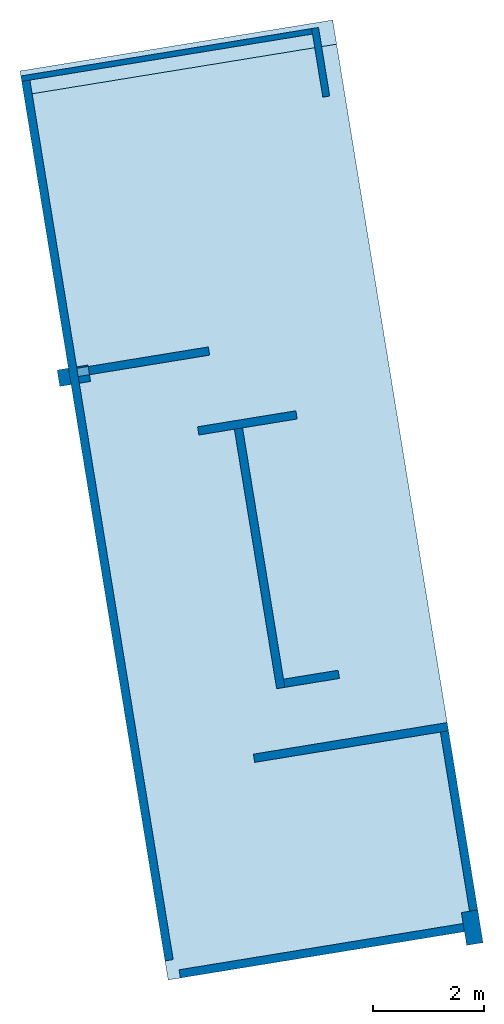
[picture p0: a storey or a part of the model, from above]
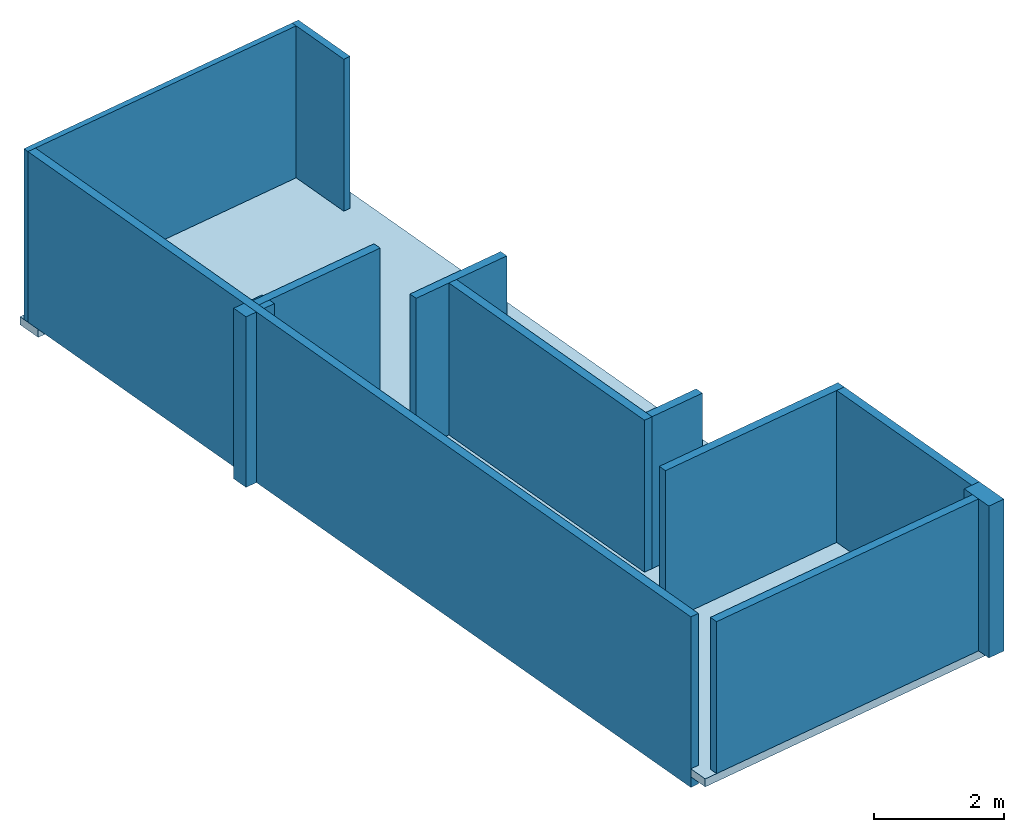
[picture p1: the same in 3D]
Properties of the parts of a building model (IFC2X3)

# File
Description: ViewDefinition [CoordinationView]
File name: BR002-350-101.1 (EDITED).IFC (Edited by Naviate Simple BIM 2022 version 6)
Time: 2026-03-27T07:42:59+01:00
Author: laura
Organization: Avinor
Written by: ODA SDAI 24.12
Made in: Autodesk Revit 25.4.41.14 (ENU) - IFC 25.4.0.27

# IfcProject, 01. Avinor Drift
LongName: Helikopter Terminal; Phase: Som bygget

# IfcSite, Default
RefLatitude: 60, 17, 20, 899658; RefLongitude: 5, 13, 37, 654037; RefElevation: 0 mm
Text - 01_Modellfil: br002-a-200-1-0001; 02_IfcSite: Bergen Lufthavn, Flesland
Other - Project Number: 01. Avinor Drift; Project Address: Bergen lufthavn Flesland; Category: Project Information; Project Status: Som bygget; Client Name: Avinor AS; Project Issue Date: 14.04.16; Project Name: Helikopter Terminal
Identity Data - Author: FDVU; Organization Name: Avinor AS; Workset: Project Info; Organization Description: D&I; Building Name: br002

# IfcBuilding, br002
LongName: br002
Pset_BuildingCommon - NumberOfStoreys: 9
Text - 01_Modellfil: br002-a-200-1-0001; 02_IfcSite: Bergen Lufthavn, Flesland
Other - Project Number: 01. Avinor Drift; Project Address: Bergen lufthavn Flesland; Category: Project Information; Project Status: Som bygget; Client Name: Avinor AS; Project Issue Date: 14.04.16; Project Name: Helikopter Terminal
Identity Data - Author: FDVU; Organization Name: Avinor AS; Workset: Project Info; Organization Description: D&I; Building Name: br002

# IfcBuildingStorey: Level:8mm Head (2)
In: br002
Other - Family and Type: Level: 8mm Head; Type Id: 305; Category: Levels; Family: Level; Type: 8mm Head
Graphics(Type) - Line Pattern: Centre; Symbol: M_Level Head - Circle; Color: 0; Symbol at End 1 Default: no; Symbol at End 2 Default: yes; Line Weight: 1
Identity Data - Structural: no; Building Story: yes; Workset: Shared Levels and Grids
Constraints(Type) - Elevation Base: Project Base Point
Identity Data(Type) - Workset: Level Types; Type Name: 8mm Head
Other(Type) - Category: Levels; Family Name: Level
Name | LongName = Identity Data, Name | Elevation (mm) | Computation Height (mm) | Constraints, Elevation (mm)
H01 | H01 | 3850 | 350 | 52210 | Pset_ProductRequirements - Name: H01; sets with these values: 2
Tak | Tak | 7600 | 0 | 55960 | Pset_AirSideSystemInformation - Name: Tak; sets with these values: 2

# IfcColumn: M_Rectangular Column:563 x 300 mm, M_Rectangular Column:563 x 300 mm:563376
In: H01
Type - PredefinedType: COLUMN; Material: Metal Deck
Type - Other - Category: Columns; Family Name: M_Rectangular Column
Type - Dimensions - Depth: 563 mm; Offset Base: 0 mm; Offset Top: 0 mm; Width: 300 mm
Type - Graphics - Coarse Scale Fill Color: 0
Type - Identity Data - OmniClass Number: 23.25.30.11.14.11; OmniClass Title: Columns; Type Name: 563 x 300 mm; Workset: Family : Columns : M_Rectangular Column
Phasing - Phase Created: Eksisterende
Other - Type Id: 564620; Family and Type: M_Rectangular Column: 563 x 300 mm; Family: M_Rectangular Column; Type: 563 x 300 mm
Dimensions - Volume: 0.308201 m3
Pset_QuantityTakeOff - Reference: 563 x 300 mm; sets with these values: 2
ePset_SimplebimBasicQuantities - Volume, net (Simplebim): 0.308201 m3; Depth (Simplebim): 563 mm; Weight, as steel (Simplebim): 2419.38 kg; Area, sides, net (Simplebim): 6.80525 m2; Width (Simplebim): 300 mm; Height (Simplebim): 3200 mm
ePset_LocationTool - Splitting: ORIGINAL
Constraints - Base Offset: 0 mm; Room Bounding: yes; Top Offset: 0 mm; Moves With Grids: yes; Top Level: H02; Base Level: H01; Level: H01
Pset_ColumnCommon - IsExternal: no; Reference: 563 x 300 mm
Identity Data - Workset: ARK
ePset_Simplebim - Assembly Level: Leaf

# IfcColumn: M_Rectangular Column:600 x 300 mm, M_Rectangular Column:600 x 300 mm:563728
In: H01
Type - PredefinedType: COLUMN; Material: Metal Deck
Type - Other - Category: Columns; Family Name: M_Rectangular Column
Type - Dimensions - Depth: 600 mm; Offset Base: 0 mm; Offset Top: 0 mm; Width: 300 mm
Type - Graphics - Coarse Scale Fill Color: 0
Type - Identity Data - OmniClass Number: 23.25.30.11.14.11; OmniClass Title: Columns; Type Name: 600 x 300 mm; Workset: Family : Columns : M_Rectangular Column
Phasing - Phase Created: Eksisterende
Identity Data - Workset: RIB
Constraints - Room Bounding: yes; Top Offset: 0 mm; Moves With Grids: yes; Top Level: H02; Base Level: H01; Level: H01; Base Offset: 350 mm
Pset_QuantityTakeOff - Reference: 600 x 300 mm; sets with these values: 2
Other - Family and Type: M_Rectangular Column: 600 x 300 mm; Type Id: 562945; Family: M_Rectangular Column; Type: 600 x 300 mm
ePset_SimplebimBasicQuantities - Area, sides, net (Simplebim): 5.13 m2; Volume, net (Simplebim): 0.513 m3; Weight, as steel (Simplebim): 4027.05 kg; Width (Simplebim): 300 mm; Depth (Simplebim): 600 mm; Height (Simplebim): 2850 mm
Dimensions - Volume: 0.513 m3
ePset_LocationTool - Splitting: ORIGINAL
Pset_ColumnCommon - IsExternal: no; Reference: 600 x 300 mm
ePset_Simplebim - Assembly Level: Leaf

# IfcRoof: Basic Roof:Sarnafil Tak, Basic Roof:Sarnafil Tak:751543
In: Tak
Material: Asphalt, Bitumen 20 mm, Rigid insulation 50 mm, Structure, Steel Bar Joist Layer 130 mm
Phasing - Phase Created: Eksisterende
Identity Data - Workset: ARK
Other - Type Id: 813923; Family: Basic Roof; Family and Type: Basic Roof: Sarnafil Tak; Category: Roofs; Type: Sarnafil Tak
Constraints - Related to Mass: no; Room Bounding: no; Base Offset From Level: 0 mm; Cutoff Offset: 0 mm; Base Level: Tak
Construction - Rafter or Truss: Truss; Rafter Cut: Plumb Cut; Fascia Depth: 0 mm; Maximum Ridge Height: 7800 mm
ePset_SimplebimBasicQuantities - Volume, net (Simplebim): 258.627 m3; Height: 200 mm; Width: 38150 mm; Length: 40660 mm
ePset_Simplebim - Assembly Level: Topmost
Pset_QuantityTakeOff - Reference: Sarnafil Tak
Dimensions - Area: 1293.14 m2; Volume: 258.627 m3; Slope: 0; Thickness: 200 mm
Pset_RoofCommon - TotalArea: 1293.14 m2; ProjectedArea: 1410.86 m2; IsExternal: yes; Reference: Sarnafil Tak

# IfcSlab: Basic Roof:Sarnafil Tak, Basic Roof:Sarnafil Tak:751543:1
In: Tak
Type - PredefinedType: ROOF
Type - Other - Category: Roofs; Family Name: Basic Roof
Type - Construction - Default Thickness: 200 mm
Type - Graphics - Coarse Scale Fill Color: 0
Type - Identity Data - Type Name: Sarnafil Tak; Workset: Roof Types
Type - Analytical Properties - Absorptance: 0.7; Roughness: 3; Heat Transfer Coefficient (U): 0.150467 W/K/m2; Thermal Mass: 40991; Thermal Resistance (R): 6.64596
Type - Pset_SlabCommon - ThermalTransmittance: 0.150467 W/K/m2
ePset_Simplebim - Assembly Level: Leaf
Pset_SlabCommon - IsExternal: yes; Reference: Sarnafil Tak
Pset_ReinforcementBarPitchOfSlab - Reference: Sarnafil Tak; sets with these values: 2
ePset_LocationTool - Splitting: RESULT
ePset_SimplebimBasicQuantities - Volume, net (Simplebim): 18.1 m3; Area, sides, net (Simplebim): 8.7 m2; Perimeter (Simplebim): 43500 mm; Thickness (Simplebim): 200 mm; Area, top, net (Simplebim): 90.5 m2; Area, largest surface, net (Simplebim): 90.5 m2

# IfcSlab: Floor:Betong 150mm (2)
In: H01
Type - PredefinedType: FLOOR; Material: Concrete, Cast In Situ 150 mm
Type - Other - Category: Floors; Family Name: Floor
Type - Construction - Function: Interior; Default Thickness: 150 mm
Type - Graphics - Coarse Scale Fill Color: 0
Type - Identity Data - Type Name: Betong 150mm; Workset: Floor Types
Type - Materials and Finishes - Structural Material: Concrete, Cast In Situ
Type - Analytical Properties - Absorptance: 0.7; Roughness: 3; Heat Transfer Coefficient (U): 6.97333 W/K/m2; Thermal Mass: 226665; Thermal Resistance (R): 0.143403
Type - Pset_SlabCommon - ThermalTransmittance: 6.97333 W/K/m2
ePset_Simplebim - Assembly Level: Leaf
ePset_LocationTool - Splitting: RESULT
Identity Data - Workset: ARK; Has Association: no
Other - Type: Betong 150mm; Family and Type: Floor: Betong 150mm; Type Id: 339; Family: Floor
Phasing - Phase Created: Eksisterende
Structural - Structural: no
Pset_SlabCommon - LoadBearing: no; IsExternal: no; Reference: Betong 150mm
Pset_QuantityTakeOff - Reference: Betong 150mm; sets with these values: 2
Constraints - Related to Mass: no; Room Bounding: yes; Level: H01
ePset_SimplebimBasicQuantities - Thickness (Simplebim): 150 mm
Name (Floor:Betong 150mm:...) | Perimeter (Simplebim) (mm) | Area, sides, net (Simplebim) (m2) | Area, top, net (Simplebim) (m2) | Area, largest surface, net (Simplebim) (m2) | Volume, net (Simplebim) (m3)
452084 | 12334.1 | 1.85011 | 2.53044 | 2.53045 | 0.379567
748018 | 44550 | 6.6825 | 94.7487 | 94.7488 | 14.2123

# IfcWall: Basic Wall:E 01 100 mm Innervegg, Basic Wall:E 01 100 mm Innervegg:560488
In: H01
Type - PredefinedType: STANDARD; Material: Gypsum Wall Board 13 mm, Structure, Timber Joist/Rafter Layer 74 mm, Gypsum Wall Board 13 mm
Type - Other - Category: Walls; Family Name: Basic Wall
Type - Construction - Function: Interior; Width: 100 mm; Wrapping at Ends: Exterior; Wrapping at Inserts: Both
Type - Graphics - Coarse Scale Fill Color: 0
Type - Identity Data - Type Mark: E01; Type Name: E 01 100 mm Innervegg; Workset: Wall Types
Type - Materials and Finishes - Structural Material: Structure, Timber Joist/Rafter Layer
Type - Analytical Properties - Absorptance: 0.7; Heat Transfer Coefficient (U): 0.333333 W/K/m2; Roughness: 3; Thermal Mass: 24113.1; Thermal Resistance (R): 3
Type - Pset_WallCommon - ThermalTransmittance: 0.333333 W/K/m2
ePset_Simplebim - Assembly Level: Leaf
Other - Family and Type: Basic Wall: E 01 100 mm Innervegg; Family: Basic Wall; Type: E 01 100 mm Innervegg; Type Id: 455070
Identity Data - Workset: ARK
Pset_WallCommon - Reference: E 01 100 mm Innervegg; IsExternal: no; ExtendToStructure: no; LoadBearing: no
Constraints - Base is Attached: no; Related to Mass: no; Room Bounding: yes; Top is Attached: no; Base Constraint: H01; Location Line: Finish Face: Interior; Top Constraint: Up to level: H02
Structural - Structural Usage: Non-bearing; Structural: no
ePset_SimplebimBasicQuantities - Volume, net (Simplebim): 1.70368 m3; Area, side, gross, average (Simplebim): 17.0368 m2; Area, side, net, average (Simplebim): 17.0368 m2; Area, largest surface, net (Simplebim): 17.0368 m2; Area, side, net, smaller (Simplebim): 17.0368 m2; Area, side, gross, smaller (Simplebim): 17.0368 m2; Area, side, net, larger (Simplebim): 17.0368 m2; Area, side, gross, larger (Simplebim): 17.0368 m2; Area, side, gross, AABB (Simplebim): 17.0368 m2; Thickness (Simplebim): 100 mm; Height (Simplebim): 3200 mm; Length (Simplebim): 5324 mm
Phasing - Phase Created: Eksisterende
Pset_QuantityTakeOff - Reference: E 01 100 mm Innervegg; sets with these values: 2
ePset_LocationTool - Splitting: RESULT
Cross-Section Definition - Cross-Section: Vertical

# IfcWall: Basic Wall:E 05 Betong 150 mm, Basic Wall:E 05 Betong 150 mm:811328
In: Tak
Type - PredefinedType: STANDARD; Material: Concrete, Cast In Situ 150 mm
Type - Other - Category: Walls; Family Name: Basic Wall
Type - Construction - Function: Exterior; Width: 150 mm; Wrapping at Ends: Exterior; Wrapping at Inserts: Both
Type - Graphics - Coarse Scale Fill Color: 12632256; Coarse Scale Fill Pattern: <Solid fill>
Type - Identity Data - Type Mark: E05 150mm; Type Name: E 05 Betong 150 mm; Workset: Wall Types
Type - Materials and Finishes - Structural Material: Concrete, Cast In Situ
Type - Analytical Properties - Absorptance: 0.7; Heat Transfer Coefficient (U): 6.97333 W/K/m2; Roughness: 3; Thermal Mass: 226665; Thermal Resistance (R): 0.143403
Type - Pset_WallCommon - ThermalTransmittance: 6.97333 W/K/m2
ePset_Simplebim - Assembly Level: Leaf
Identity Data - Workset: ARK
Constraints - Location Line: Wall Centerline; Base is Attached: no; Related to Mass: no; Room Bounding: yes; Top is Attached: no; Base Constraint: Tak; Top Constraint: Up to level: Tak
Pset_QuantityTakeOff - Reference: E 05 Betong 150 mm; sets with these values: 2
ePset_LocationTool - Splitting: RESULT
Structural - Structural Usage: Non-bearing; Structural: no
Phasing - Phase Created: Eksisterende
ePset_SimplebimBasicQuantities - Area, side, gross, larger (Simplebim): 2.57625 m2; Area, side, net, larger (Simplebim): 2.57625 m2; Area, side, gross, smaller (Simplebim): 2.57625 m2; Area, side, net, smaller (Simplebim): 2.57625 m2; Area, largest surface, net (Simplebim): 2.57625 m2; Area, side, net, average (Simplebim): 2.57625 m2; Area, side, gross, average (Simplebim): 2.57625 m2; Area, side, gross, AABB (Simplebim): 2.57625 m2; Thickness (Simplebim): 150 mm; Height (Simplebim): 450 mm; Length (Simplebim): 5725 mm; Volume, net (Simplebim): 0.386437 m3
Other - Family: Basic Wall; Type Id: 442479; Family and Type: Basic Wall: E 05 Betong 150 mm; Type: E 05 Betong 150 mm
Pset_WallCommon - IsExternal: yes; ExtendToStructure: no; LoadBearing: no; Reference: E 05 Betong 150 mm
Cross-Section Definition - Cross-Section: Vertical

# IfcWallStandardCase: Basic Wall:A 03 150 mm Planja Sand. (7)
In: H01
Type - PredefinedType: STANDARD; Material: Metal Deck 5 mm, Polyurethane Foam 140 mm, Metal Deck 5 mm
Type - Other - Category: Walls; Family Name: Basic Wall
Type - Construction - Function: Exterior; Width: 150 mm; Wrapping at Ends: Exterior; Wrapping at Inserts: Both
Type - Graphics - Coarse Scale Fill Color: 12632256; Coarse Scale Fill Pattern: <Solid fill>
Type - Identity Data - Type Mark: A03; Type Name: A 03 150 mm Planja Sand.; Workset: Wall Types
Type - Materials and Finishes - Structural Material: Polyurethane Foam
Type - Analytical Properties - Absorptance: 0.7; Heat Transfer Coefficient (U): 0.22856 W/K/m2; Roughness: 3; Thermal Mass: 45179.5; Thermal Resistance (R): 4.37522
Type - Pset_WallCommon - ThermalTransmittance: 0.22856 W/K/m2
ePset_Simplebim - Assembly Level: Leaf
ePset_LocationTool - Splitting: ORIGINAL
Identity Data - Workset: ARK
Pset_QuantityTakeOff - Reference: A 03 150 mm Planja Sand.; sets with these values: 2
Constraints - Location Line: Wall Centerline; Base Extension Distance: 0 mm; Base is Attached: no; Related to Mass: no; Room Bounding: yes; Top Extension Distance: 0 mm; Top is Attached: no; Top Offset: 0 mm; Base Constraint: H01; Top Constraint: Up to level: H02
Structural - Structural Usage: Non-bearing; Structural: no
Phasing - Phase Created: Eksisterende
Pset_WallCommon - Reference: A 03 150 mm Planja Sand.; IsExternal: yes; ExtendToStructure: no; LoadBearing: no
Other - Family: Basic Wall; Type: A 03 150 mm Planja Sand.; Family and Type: Basic Wall: A 03 150 mm Planja Sand.; Type Id: 562544
Cross-Section Definition - Cross-Section: Vertical
ePset_SimplebimBasicQuantities - Thickness (Simplebim): 150 mm
Name (Basic Wall:A 03 150 mm Planja Sand.:...) | Base Offset (mm) | Unconnected Height (mm) = Height (Simplebim) (mm) | Volume (m3) = Volume, net (Simplebim) (m3) | Area (m2) = Area, side, gross, AABB (Simplebim) (m2) | Length (mm) | Area, side, gross, larger (Simplebim) (m2) = Area, side, net, larger (Simplebim) (m2) = Area, side, gross, smaller (Simplebim) (m2) = Area, side, net, smaller (Simplebim) (m2) = Area, largest surface, net (Simplebim) (m2) = Area, side, net, average (Simplebim) (m2) = Area, side, gross, average (Simplebim) (m2) | Length (Simplebim) (mm)
562806 | 0 | 3200 | 7.728 | 51.52 | 16150 | 51.52 | 16100
564712 | 350 | 2850 | 1.02878 | 6.85852 | 2481.5 | 6.85853 | 2406.5
564821 | 350 | 2850 | 0.7695 | 5.13 | 1800 | 5.13 | 1800
564865 | 350 | 2850 | 2.03062 | 13.5375 | 4750 | 13.5375 | 4750
564906 | 350 | 2850 | 0.4275 | 2.85 | 1075 | 2.85 | 1000
564973 | 350 | 2850 | 1.51669 | 10.1113 | 3472.81 | 10.1113 | 3547.81
565062 | 350 | 2850 | 1.4022 | 9.348 | 3355 | 9.348 | 3280

# IfcWallStandardCase: Basic Wall:B 09 126mm Halvvegg, Basic Wall:B 09 126mm Halvvegg:560303
In: H01
Type - PredefinedType: STANDARD; Material: Gypsum Wall Board 15 mm, Structure, Timber Joist/Rafter Layer 96 mm, Gypsum Wall Board 15 mm
Type - Other - Category: Walls; Family Name: Basic Wall
Type - Construction - Function: Interior; Width: 126 mm; Wrapping at Inserts: Do not wrap
Type - Graphics - Coarse Scale Fill Color: 0
Type - Identity Data - Type Mark: B09; Type Name: B 09 126mm Halvvegg; Workset: Wall Types
Type - Materials and Finishes - Structural Material: Structure, Timber Joist/Rafter Layer
Type - Analytical Properties - Absorptance: 0.7; Heat Transfer Coefficient (U): 0.257324 W/K/m2; Roughness: 3; Thermal Mass: 27835.6; Thermal Resistance (R): 3.88615
Type - Pset_WallCommon - ThermalTransmittance: 0.257324 W/K/m2
Constraints - Base Extension Distance: 0 mm; Base is Attached: no; Base Offset: 0 mm; Related to Mass: no; Room Bounding: yes; Top Extension Distance: 0 mm; Top is Attached: no; Top Offset: 0 mm; Base Constraint: H01; Location Line: Finish Face: Interior; Unconnected Height: 3200 mm; Top Constraint: Up to level: H02
ePset_Simplebim - Assembly Level: Leaf
Identity Data - Workset: ARK
Other - Type: B 09 126mm Halvvegg; Family: Basic Wall; Type Id: 559783; Family and Type: Basic Wall: B 09 126mm Halvvegg
Pset_WallCommon - Reference: B 09 126mm Halvvegg; IsExternal: no; ExtendToStructure: no; LoadBearing: no
Structural - Structural Usage: Non-bearing; Structural: no
Phasing - Phase Created: Eksisterende
ePset_SimplebimBasicQuantities - Height (Simplebim): 3200 mm; Length (Simplebim): 1255.99 mm; Volume, net (Simplebim): 0.506415 m3; Thickness (Simplebim): 126 mm; Area, largest surface, net (Simplebim): 4.01917 m2; Area, side, net, average (Simplebim): 4.01917 m2; Area, side, gross, average (Simplebim): 4.01917 m2; Area, side, gross, larger (Simplebim): 4.01917 m2; Area, side, net, larger (Simplebim): 4.01917 m2; Area, side, gross, smaller (Simplebim): 4.01917 m2; Area, side, net, smaller (Simplebim): 4.01917 m2; Area, side, gross, AABB (Simplebim): 4.01917 m2
Pset_QuantityTakeOff - Reference: B 09 126mm Halvvegg; sets with these values: 2
ePset_LocationTool - Splitting: ORIGINAL
Dimensions - Length: 1205.99 mm; Volume: 0.506415 m3; Area: 4.01917 m2
Cross-Section Definition - Cross-Section: Vertical

# IfcWallStandardCase: Basic Wall:E 01 150 mm Innervegg, Basic Wall:E 01 150 mm Innervegg:565798
In: H01
Type - PredefinedType: STANDARD; Material: Gypsum Wall Board 13 mm, Gypsum Wall Board 13 mm, Rock Wool 49 mm, Rock Wool(1) 49 mm, Gypsum Wall Board 13 mm, Gypsum Wall Board 13 mm
Type - Other - Category: Walls; Family Name: Basic Wall
Type - Construction - Function: Interior; Width: 150 mm; Wrapping at Ends: Exterior; Wrapping at Inserts: Both
Type - Graphics - Coarse Scale Fill Color: 0
Type - Identity Data - Type Mark: E01 150mm; Type Name: E 01 150 mm Innervegg; Workset: Wall Types
Type - Materials and Finishes - Structural Material: Rock Wool
Type - Analytical Properties - Absorptance: 0.7; Heat Transfer Coefficient (U): 0.337569 W/K/m2; Roughness: 3; Thermal Mass: 61964; Thermal Resistance (R): 2.96235
Type - Pset_WallCommon - ThermalTransmittance: 0.337569 W/K/m2
ePset_Simplebim - Assembly Level: Leaf
Identity Data - Workset: ARK
ePset_SimplebimBasicQuantities - Height (Simplebim): 2850 mm; Thickness (Simplebim): 150 mm; Length (Simplebim): 5200 mm; Area, side, gross, average (Simplebim): 14.82 m2; Area, side, net, average (Simplebim): 14.82 m2; Area, largest surface, net (Simplebim): 14.82 m2; Area, side, net, smaller (Simplebim): 14.82 m2; Area, side, gross, smaller (Simplebim): 14.82 m2; Area, side, net, larger (Simplebim): 14.82 m2; Area, side, gross, larger (Simplebim): 14.82 m2; Area, side, gross, AABB (Simplebim): 14.82 m2; Volume, net (Simplebim): 2.223 m3
Other - Family: Basic Wall; Family and Type: Basic Wall: E 01 150 mm Innervegg; Type: E 01 150 mm Innervegg; Type Id: 531135
Pset_WallCommon - IsExternal: no; ExtendToStructure: no; LoadBearing: no; Reference: E 01 150 mm Innervegg
Structural - Structural Usage: Non-bearing; Structural: no
Phasing - Phase Created: Eksisterende
Pset_QuantityTakeOff - Reference: E 01 150 mm Innervegg; sets with these values: 2
Dimensions - Length: 5200 mm; Area: 14.82 m2; Volume: 2.223 m3
Cross-Section Definition - Cross-Section: Vertical
Constraints - Location Line: Wall Centerline; Base Extension Distance: 0 mm; Base is Attached: no; Related to Mass: no; Room Bounding: yes; Top Extension Distance: 0 mm; Top is Attached: no; Top Offset: 0 mm; Base Constraint: H01; Base Offset: 350 mm; Unconnected Height: 2850 mm; Top Constraint: Up to level: H02
ePset_LocationTool - Splitting: ORIGINAL

# IfcWallStandardCase: Basic Wall:E 05 Betong 150 mm, Basic Wall:E 05 Betong 150 mm:796313
In: Tak
Type - PredefinedType: STANDARD; Material: Concrete, Cast In Situ 150 mm
Type - Other - Category: Walls; Family Name: Basic Wall
Type - Construction - Function: Exterior; Width: 150 mm; Wrapping at Ends: Exterior; Wrapping at Inserts: Both
Type - Graphics - Coarse Scale Fill Color: 12632256; Coarse Scale Fill Pattern: <Solid fill>
Type - Identity Data - Type Mark: E05 150mm; Type Name: E 05 Betong 150 mm; Workset: Wall Types
Type - Materials and Finishes - Structural Material: Concrete, Cast In Situ
Type - Analytical Properties - Absorptance: 0.7; Heat Transfer Coefficient (U): 6.97333 W/K/m2; Roughness: 3; Thermal Mass: 226665; Thermal Resistance (R): 0.143403
Type - Pset_WallCommon - ThermalTransmittance: 6.97333 W/K/m2
ePset_Simplebim - Assembly Level: Leaf
Identity Data - Workset: ARK
Dimensions - Area: 5.575 m2; Length: 11000 mm; Volume: 0.83625 m3
Pset_QuantityTakeOff - Reference: E 05 Betong 150 mm; sets with these values: 2
Structural - Structural Usage: Non-bearing; Structural: no
Phasing - Phase Created: Eksisterende
Constraints - Location Line: Wall Centerline; Base Extension Distance: 0 mm; Base is Attached: no; Related to Mass: no; Room Bounding: yes; Top Extension Distance: 0 mm; Top is Attached: no; Top Offset: 0 mm; Base Constraint: Tak; Base Offset: 150 mm; Unconnected Height: 500 mm
Other - Family: Basic Wall; Type Id: 442479; Family and Type: Basic Wall: E 05 Betong 150 mm; Type: E 05 Betong 150 mm
Pset_WallCommon - IsExternal: yes; ExtendToStructure: no; LoadBearing: no; Reference: E 05 Betong 150 mm
Cross-Section Definition - Cross-Section: Vertical
ePset_LocationTool - Splitting: ORIGINAL
ePset_SimplebimBasicQuantities - Area, largest surface, net (Simplebim): 5.575 m2; Area, side, gross, average (Simplebim): 5.575 m2; Area, side, net, average (Simplebim): 5.575 m2; Area, side, net, larger (Simplebim): 5.575 m2; Area, side, gross, larger (Simplebim): 5.575 m2; Area, side, net, smaller (Simplebim): 5.575 m2; Area, side, gross, smaller (Simplebim): 5.575 m2; Area, side, gross, AABB (Simplebim): 5.575 m2; Length (Simplebim): 11150 mm; Height (Simplebim): 500 mm; Thickness (Simplebim): 150 mm; Volume, net (Simplebim): 0.83625 m3
